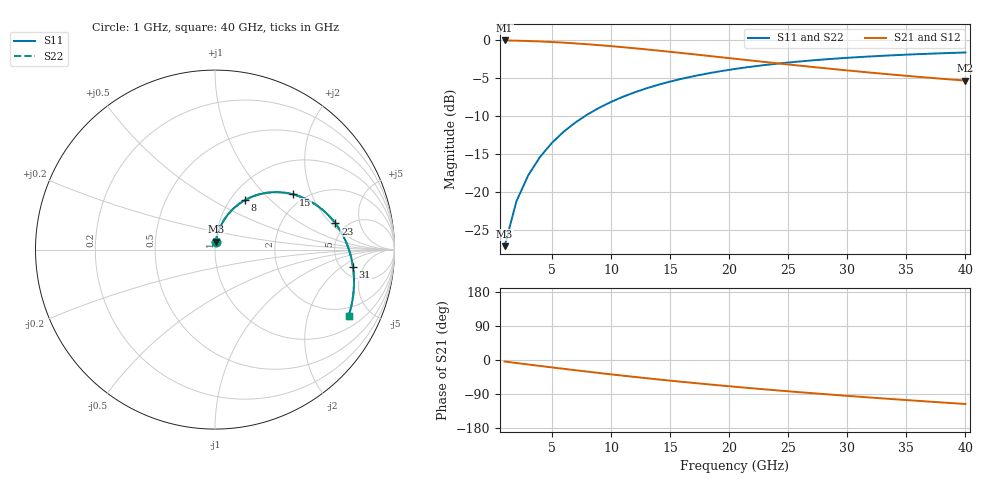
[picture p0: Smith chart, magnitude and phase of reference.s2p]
! circuitRF F0 spike reference -- case A, Palace, perimeter-matched hexagon with 2d wedge feet
! Palace postpro/port-S.csv, dB/deg -> RI; port 1 excited only; S22 = S11 and S12 = S21 by the mirror symmetry of the geometry about x = 0
# GHz S RI R 50
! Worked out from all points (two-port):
!   40 points, 1 GHz to 40 GHz, reference 50 ohm
!   highest |S21| = -0.02 dB at 1 GHz (marker M1); lowest = -5.3 dB at 40 GHz (marker M2)
!   |S21| within 3 dB of the highest: start of sweep to 24.02 GHz
!   lowest |S11| = -27.1 dB at 1 GHz (marker M3), VSWR 1.09, Z = 50.3 + j4.41 ohm
!   |S11| at or under -10 dB: start of sweep to 7.789 GHz
!   |S22| runs from -27.1 to -1.6 dB; largest |S21 - S12| = 0
!   S11 on the Smith chart (normalised r, x): 1 GHz: 1.01, +0.09; 8 GHz: 1.17, +0.72; 15 GHz: 1.74, +1.50; 23 GHz: 4.09, +2.25; 31 GHz: 6.35, -3.10; 40 GHz: 1.53, -3.66
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1  0.00444 0.0438  0.9952 -0.0695  0.9952 -0.0695  0.00444 0.0438
2  0.0139 0.0858  0.9848 -0.1371  0.9848 -0.1371  0.0139 0.0858
3  0.0288 0.1259  0.9682 -0.2028  0.9682 -0.2028  0.0288 0.1259
4  0.0488 0.1634  0.9459 -0.2658  0.9459 -0.2658  0.0488 0.1634
5  0.0733 0.1977  0.9184 -0.3256  0.9184 -0.3256  0.0733 0.1977
6  0.1019 0.2283  0.8861 -0.3817  0.8861 -0.3817  0.1019 0.2283
7  0.1339 0.2548  0.8498 -0.4335  0.8498 -0.4335  0.1339 0.2548
8  0.1687 0.2769  0.8101 -0.4808  0.8101 -0.4808  0.1687 0.2769
9  0.2055 0.2945  0.7677 -0.5235  0.7677 -0.5235  0.2055 0.2945
11  0.2829 0.3159  0.6771 -0.5945  0.6771 -0.5945  0.2829 0.3159
12  0.3223 0.3199  0.6302 -0.6231  0.6302 -0.6231  0.3223 0.3199
14  0.3998 0.3154  0.5357 -0.6672  0.5357 -0.6672  0.3998 0.3154
15  0.4372 0.3074  0.4888 -0.6831  0.4888 -0.6831  0.4372 0.3074
18  0.5401 0.264  0.3539 -0.7101  0.3539 -0.7101  0.5401 0.264
21  0.6253 0.1981  0.2311 -0.7119  0.2311 -0.7119  0.6253 0.1981
23  0.6712 0.1455  0.1573 -0.7028  0.1573 -0.7028  0.6712 0.1455
25  0.7082 0.0881  0.0901 -0.6875  0.0901 -0.6875  0.7082 0.0881
27  0.7365 0.0276  0.0292 -0.6675  0.0292 -0.6675  0.7365 0.0276
31  0.7691 -0.0975  -0.0746 -0.6181  -0.0746 -0.6181  0.7691 -0.0975
34  0.7745 -0.1914  -0.1388 -0.5762  -0.1388 -0.5762  0.7745 -0.1914
37  0.7657 -0.2826  -0.193 -0.5323  -0.193 -0.5323  0.7657 -0.2826
40  0.7445 -0.3697  -0.2386 -0.4876  -0.2386 -0.4876  0.7445 -0.3697
